###############################################################
#  Generated by:      Cadence Innovus 20.13-s083_1
#  OS:                Linux x86_64(Host ID iron-502-26)
#  Generated on:      Fri Jul  1 13:20:40 2022
#  Design:            puf_super
#  Command:           write_lef_abstract -specifyTopLayer 5 -PGPinLayers {5 6} -noCutObs -extractBlockObs -stripePin results/puf_super.lef
###############################################################

VERSION 5.8 ;

BUSBITCHARS "[]" ;
DIVIDERCHAR "/" ;

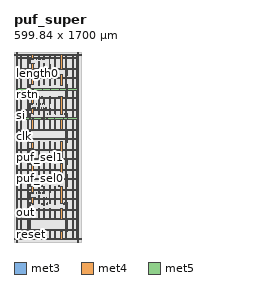
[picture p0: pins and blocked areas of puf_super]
MACRO puf_super
  CLASS BLOCK ;
  SIZE 599.840000 BY 1700.000000 ;
  FOREIGN puf_super 0.000000 0.000000 ;
  ORIGIN 0 0 ;
  SYMMETRY X Y R90 ;
  PIN reset
    DIRECTION INPUT ;
    USE SIGNAL ;
    ANTENNAPARTIALMETALAREA 0.4194 LAYER met3  ;
    ANTENNAPARTIALMETALSIDEAREA 2.68 LAYER met3  ;
    ANTENNAPARTIALCUTAREA 0.04 LAYER via3  ;
    ANTENNAPARTIALMETALAREA 3.9618 LAYER met4  ;
    ANTENNAPARTIALMETALSIDEAREA 21.6 LAYER met4  ;
    ANTENNAMODEL OXIDE1 ;
    ANTENNAGATEAREA 0.495 LAYER met4  ;
    ANTENNAMAXAREACAR 55.6044 LAYER met4  ;
    ANTENNAMAXSIDEAREACAR 280.796 LAYER met4  ;
    ANTENNAMAXCUTCAR 0.323838 LAYER via4  ;
    PORT
      LAYER met3 ;
        RECT 0.000000 0.520000 0.800000 0.820000 ;
    END
  END reset
  PIN clk
    DIRECTION INPUT ;
    USE SIGNAL ;
    ANTENNAPARTIALMETALAREA 15.6204 LAYER met3  ;
    ANTENNAPARTIALMETALSIDEAREA 83.304 LAYER met3  ;
    ANTENNAMODEL OXIDE1 ;
    ANTENNAGATEAREA 1.152 LAYER met3  ;
    ANTENNAMAXAREACAR 14.5083 LAYER met3  ;
    ANTENNAMAXSIDEAREACAR 75.1606 LAYER met3  ;
    ANTENNAMAXCUTCAR 0.0793403 LAYER via3  ;
    PORT
      LAYER met3 ;
        RECT 0.000000 944.190000 0.800000 944.490000 ;
    END
  END clk
  PIN si
    DIRECTION INPUT ;
    USE SIGNAL ;
    ANTENNAPARTIALMETALAREA 23.0986 LAYER met3  ;
    ANTENNAPARTIALMETALSIDEAREA 123.184 LAYER met3  ;
    ANTENNAPARTIALCUTAREA 0.04 LAYER via3  ;
    ANTENNAPARTIALMETALAREA 0.6516 LAYER met4  ;
    ANTENNAPARTIALMETALSIDEAREA 4.416 LAYER met4  ;
    ANTENNAMODEL OXIDE1 ;
    ANTENNAGATEAREA 0.126 LAYER met4  ;
    ANTENNAMAXAREACAR 91.5542 LAYER met4  ;
    ANTENNAMAXSIDEAREACAR 443.786 LAYER met4  ;
    ANTENNAMAXCUTCAR 1.04286 LAYER via4  ;
    PORT
      LAYER met3 ;
        RECT 0.000000 1132.680000 0.800000 1132.980000 ;
    END
  END si
  PIN rstn
    DIRECTION INPUT ;
    USE SIGNAL ;
    ANTENNAPARTIALMETALAREA 33.1464 LAYER met3  ;
    ANTENNAPARTIALMETALSIDEAREA 176.776 LAYER met3  ;
    ANTENNAMODEL OXIDE1 ;
    ANTENNAGATEAREA 2.733 LAYER met3  ;
    ANTENNAMAXAREACAR 44.3132 LAYER met3  ;
    ANTENNAMAXSIDEAREACAR 222.668 LAYER met3  ;
    ANTENNAMAXCUTCAR 0.361584 LAYER via3  ;
    PORT
      LAYER met3 ;
        RECT 0.000000 1321.780000 0.800000 1322.080000 ;
    END
  END rstn
  PIN puf_sel1
    DIRECTION INPUT ;
    USE SIGNAL ;
    ANTENNAPARTIALMETALAREA 1.9584 LAYER met3  ;
    ANTENNAPARTIALMETALSIDEAREA 10.44 LAYER met3  ;
    ANTENNAMODEL OXIDE1 ;
    ANTENNAGATEAREA 0.81 LAYER met3  ;
    ANTENNAMAXAREACAR 69.6004 LAYER met3  ;
    ANTENNAMAXSIDEAREACAR 345.132 LAYER met3  ;
    ANTENNAMAXCUTCAR 0.257059 LAYER via3  ;
    PORT
      LAYER met3 ;
        RECT 0.000000 755.090000 0.800000 755.390000 ;
    END
  END puf_sel1
  PIN puf_sel0
    DIRECTION INPUT ;
    USE SIGNAL ;
    ANTENNAPARTIALMETALAREA 14.3784 LAYER met3  ;
    ANTENNAPARTIALMETALSIDEAREA 76.68 LAYER met3  ;
    ANTENNAMODEL OXIDE1 ;
    ANTENNAGATEAREA 1.5525 LAYER met3  ;
    ANTENNAMAXAREACAR 55.5734 LAYER met3  ;
    ANTENNAMAXSIDEAREACAR 278.761 LAYER met3  ;
    ANTENNAMAXCUTCAR 0.233442 LAYER via3  ;
    PORT
      LAYER met3 ;
        RECT 0.000000 566.600000 0.800000 566.900000 ;
    END
  END puf_sel0
  PIN length1
    DIRECTION INPUT ;
    USE SIGNAL ;
    ANTENNAPARTIALMETALAREA 31.7664 LAYER met3  ;
    ANTENNAPARTIALMETALSIDEAREA 169.416 LAYER met3  ;
    ANTENNAMODEL OXIDE1 ;
    ANTENNAGATEAREA 1.1145 LAYER met3  ;
    ANTENNAMAXAREACAR 150.071 LAYER met3  ;
    ANTENNAMAXSIDEAREACAR 755.32 LAYER met3  ;
    ANTENNAMAXCUTCAR 0.277205 LAYER via3  ;
    PORT
      LAYER met3 ;
        RECT 0.000000 1698.760000 0.800000 1699.060000 ;
    END
  END length1
  PIN length0
    DIRECTION INPUT ;
    USE SIGNAL ;
    ANTENNAPARTIALMETALAREA 28.0404 LAYER met3  ;
    ANTENNAPARTIALMETALSIDEAREA 149.544 LAYER met3  ;
    ANTENNAMODEL OXIDE1 ;
    ANTENNAGATEAREA 1.023 LAYER met3  ;
    ANTENNAMAXAREACAR 140.376 LAYER met3  ;
    ANTENNAMAXSIDEAREACAR 708.093 LAYER met3  ;
    ANTENNAMAXCUTCAR 0.428596 LAYER via3  ;
    PORT
      LAYER met3 ;
        RECT 0.000000 1510.270000 0.800000 1510.570000 ;
    END
  END length0
  PIN out
    DIRECTION OUTPUT ;
    USE SIGNAL ;
    ANTENNADIFFAREA 0.3406 LAYER met3  ;
    ANTENNAPARTIALMETALAREA 8.5824 LAYER met3  ;
    ANTENNAPARTIALMETALSIDEAREA 45.768 LAYER met3  ;
    PORT
      LAYER met3 ;
        RECT 0.000000 189.010000 0.800000 189.310000 ;
    END
  END out
  PIN so
    DIRECTION OUTPUT ;
    USE SIGNAL ;
    ANTENNAPARTIALMETALAREA 141.351 LAYER met3  ;
    ANTENNAPARTIALMETALSIDEAREA 753.856 LAYER met3  ;
    ANTENNAPARTIALCUTAREA 0.08 LAYER via3  ;
    ANTENNAPARTIALMETALAREA 118.617 LAYER met4  ;
    ANTENNAPARTIALMETALSIDEAREA 629.912 LAYER met4  ;
    ANTENNAPARTIALCUTAREA 0.64 LAYER via4  ;
    ANTENNADIFFAREA 0.4455 LAYER met5  ;
    ANTENNAPARTIALMETALAREA 7.44 LAYER met5  ;
    ANTENNAPARTIALMETALSIDEAREA 15 LAYER met5  ;
    PORT
      LAYER met3 ;
        RECT 0.000000 377.500000 0.800000 377.800000 ;
    END
  END so
  PIN vssd1
    DIRECTION INOUT ;
    USE GROUND ;
    PORT
      LAYER met4 ;
        RECT 577.520000 1696.900000 580.620000 1700.000000 ;
    END
    PORT
      LAYER met4 ;
        RECT 577.520000 0.000000 580.620000 3.100000 ;
    END
    PORT
      LAYER met4 ;
        RECT 19.220000 1696.900000 22.320000 1700.000000 ;
    END
    PORT
      LAYER met4 ;
        RECT 19.220000 0.000000 22.320000 3.100000 ;
    END
    PORT
      LAYER met5 ;
        RECT 596.740000 1677.640000 599.840000 1680.740000 ;
    END
    PORT
      LAYER met5 ;
        RECT 0.000000 1677.640000 3.100000 1680.740000 ;
    END
    PORT
      LAYER met5 ;
        RECT 596.740000 19.260000 599.840000 22.360000 ;
    END
    PORT
      LAYER met5 ;
        RECT 0.000000 19.260000 3.100000 22.360000 ;
    END

# P/G power stripe data as pin
    PORT
      LAYER met4 ;
        RECT 19.220000 0.000000 22.320000 1700.000000 ;
        RECT 160.000000 836.695000 170.000000 894.600000 ;
        RECT 260.000000 836.695000 270.000000 894.600000 ;
        RECT 60.000000 19.260000 70.000000 1680.740000 ;
        RECT 577.520000 0.000000 580.620000 1700.000000 ;
        RECT 360.000000 747.890000 370.000000 894.600000 ;
        RECT 460.000000 19.260000 470.000000 1680.740000 ;
        RECT 560.000000 19.260000 570.000000 1680.740000 ;
        RECT 142.800000 392.800000 144.600000 438.495000 ;
        RECT 160.000000 206.320000 170.000000 294.600000 ;
        RECT 260.000000 206.320000 270.000000 300.780000 ;
        RECT 142.800000 92.800000 144.600000 208.120000 ;
        RECT 160.000000 19.260000 170.000000 94.600000 ;
        RECT 260.000000 19.260000 270.000000 94.600000 ;
        RECT 142.800000 292.800000 144.600000 349.690000 ;
        RECT 160.000000 347.890000 170.000000 394.600000 ;
        RECT 174.985000 339.315000 176.785000 349.690000 ;
        RECT 178.405000 392.800000 180.095000 400.845000 ;
        RECT 260.000000 324.320000 270.000000 394.600000 ;
        RECT 291.655000 392.800000 293.345000 400.845000 ;
        RECT 160.000000 606.320000 170.000000 694.600000 ;
        RECT 260.000000 606.320000 270.000000 700.780000 ;
        RECT 142.800000 492.800000 144.600000 608.120000 ;
        RECT 160.000000 436.695000 170.000000 494.600000 ;
        RECT 159.485000 430.450000 161.175000 438.495000 ;
        RECT 169.585000 492.800000 171.385000 502.330000 ;
        RECT 260.000000 436.695000 270.000000 494.600000 ;
        RECT 235.005000 430.450000 236.695000 438.495000 ;
        RECT 216.165000 430.450000 217.855000 438.495000 ;
        RECT 197.275000 430.450000 198.965000 438.495000 ;
        RECT 272.715000 430.450000 274.405000 438.495000 ;
        RECT 253.865000 430.450000 255.555000 438.495000 ;
        RECT 253.005000 492.800000 254.805000 501.735000 ;
        RECT 260.000000 724.320000 270.000000 794.600000 ;
        RECT 174.985000 739.315000 176.785000 749.690000 ;
        RECT 142.800000 692.800000 144.600000 749.690000 ;
        RECT 142.800000 792.800000 144.600000 838.495000 ;
        RECT 160.000000 747.890000 170.000000 794.600000 ;
        RECT 318.655000 392.800000 320.455000 438.495000 ;
        RECT 360.000000 347.890000 370.000000 494.600000 ;
        RECT 360.000000 206.320000 370.000000 294.600000 ;
        RECT 475.940000 92.800000 477.740000 208.120000 ;
        RECT 360.000000 19.260000 370.000000 94.600000 ;
        RECT 477.120000 292.800000 478.920000 349.690000 ;
        RECT 367.485000 339.315000 369.285000 349.690000 ;
        RECT 299.985000 339.315000 301.785000 349.690000 ;
        RECT 449.985000 339.315000 451.785000 349.690000 ;
        RECT 360.000000 606.320000 370.000000 694.600000 ;
        RECT 475.940000 492.800000 477.740000 608.120000 ;
        RECT 405.505000 492.800000 407.305000 501.735000 ;
        RECT 328.005000 598.890000 329.805000 601.420000 ;
        RECT 299.985000 739.315000 301.785000 749.690000 ;
        RECT 367.485000 739.315000 369.285000 749.690000 ;
        RECT 449.985000 739.315000 451.785000 749.690000 ;
        RECT 477.120000 692.800000 478.920000 749.690000 ;
        RECT 318.655000 792.800000 320.455000 838.495000 ;
        RECT 260.000000 1236.695000 270.000000 1294.600000 ;
        RECT 160.000000 1236.695000 170.000000 1294.600000 ;
        RECT 160.000000 1006.320000 170.000000 1094.600000 ;
        RECT 260.000000 1006.320000 270.000000 1100.780000 ;
        RECT 142.800000 892.800000 144.600000 1008.120000 ;
        RECT 260.000000 1124.320000 270.000000 1194.600000 ;
        RECT 160.000000 1147.890000 170.000000 1194.600000 ;
        RECT 142.800000 1092.800000 144.600000 1149.690000 ;
        RECT 176.080000 1139.315000 177.880000 1149.690000 ;
        RECT 142.800000 1192.800000 144.600000 1238.495000 ;
        RECT 178.495000 1192.800000 180.185000 1200.845000 ;
        RECT 159.575000 1230.450000 161.265000 1238.495000 ;
        RECT 291.745000 1192.800000 293.435000 1200.845000 ;
        RECT 197.365000 1230.450000 199.055000 1238.495000 ;
        RECT 216.255000 1230.450000 217.945000 1238.495000 ;
        RECT 235.095000 1230.450000 236.785000 1238.495000 ;
        RECT 253.955000 1230.450000 255.645000 1238.495000 ;
        RECT 272.805000 1230.450000 274.495000 1238.495000 ;
        RECT 160.000000 1406.320000 170.000000 1494.600000 ;
        RECT 260.000000 1406.320000 270.000000 1500.780000 ;
        RECT 142.800000 1292.800000 144.600000 1408.120000 ;
        RECT 169.585000 1292.800000 171.385000 1302.330000 ;
        RECT 253.005000 1292.800000 254.805000 1301.735000 ;
        RECT 142.800000 1592.800000 144.600000 1638.495000 ;
        RECT 260.000000 1524.320000 270.000000 1594.600000 ;
        RECT 160.000000 1547.890000 170.000000 1594.600000 ;
        RECT 178.495000 1592.800000 180.185000 1600.845000 ;
        RECT 291.745000 1592.800000 293.435000 1600.845000 ;
        RECT 142.800000 1492.800000 144.600000 1549.690000 ;
        RECT 160.000000 1636.695000 170.000000 1680.740000 ;
        RECT 159.575000 1630.450000 161.265000 1638.495000 ;
        RECT 260.000000 1636.695000 270.000000 1680.740000 ;
        RECT 216.255000 1630.450000 217.945000 1638.495000 ;
        RECT 197.365000 1630.450000 199.055000 1638.495000 ;
        RECT 235.095000 1630.450000 236.785000 1638.495000 ;
        RECT 253.955000 1630.450000 255.645000 1638.495000 ;
        RECT 272.805000 1630.450000 274.495000 1638.495000 ;
        RECT 360.000000 1147.890000 370.000000 1294.600000 ;
        RECT 360.000000 1006.320000 370.000000 1094.600000 ;
        RECT 475.940000 892.800000 477.740000 1008.120000 ;
        RECT 368.580000 1139.315000 370.380000 1149.690000 ;
        RECT 301.080000 1139.315000 302.880000 1149.690000 ;
        RECT 480.005000 1092.800000 481.805000 1149.690000 ;
        RECT 451.080000 1139.315000 452.880000 1149.690000 ;
        RECT 319.550000 1192.800000 321.350000 1238.495000 ;
        RECT 360.000000 1406.320000 370.000000 1494.600000 ;
        RECT 475.940000 1292.800000 477.740000 1408.120000 ;
        RECT 405.505000 1292.800000 407.305000 1301.735000 ;
        RECT 328.005000 1398.890000 329.805000 1401.420000 ;
        RECT 360.000000 1547.890000 370.000000 1680.740000 ;
        RECT 319.550000 1592.800000 321.350000 1638.495000 ;
        RECT 480.005000 1492.800000 481.805000 1549.690000 ;
        RECT 159.485000 436.695000 170.000000 438.495000 ;
        RECT 160.000000 492.800000 171.385000 494.600000 ;
        RECT 159.575000 1236.695000 170.000000 1238.495000 ;
        RECT 160.000000 1292.800000 171.385000 1294.600000 ;
        RECT 159.575000 1636.695000 170.000000 1638.495000 ;
        RECT 360.000000 1147.890000 370.380000 1149.690000 ;
        RECT 252.360000 100.190000 255.450000 110.000000 ;
        RECT 168.525000 100.370000 172.445000 110.000000 ;
        RECT 178.405000 820.000000 180.095000 830.000000 ;
        RECT 159.485000 820.000000 161.175000 830.000000 ;
        RECT 197.275000 820.000000 198.965000 830.000000 ;
        RECT 216.165000 820.000000 217.855000 830.000000 ;
        RECT 235.005000 820.000000 236.695000 830.000000 ;
        RECT 253.865000 820.000000 255.555000 830.000000 ;
        RECT 272.715000 820.000000 274.405000 830.000000 ;
        RECT 291.655000 820.000000 293.345000 830.000000 ;
        RECT 404.860000 100.190000 407.950000 110.000000 ;
        RECT 327.360000 100.190000 330.450000 110.000000 ;
        RECT 168.525000 999.505000 172.445000 1000.925000 ;
        RECT 252.360000 999.505000 255.450000 1000.925000 ;
        RECT 168.525000 1360.000000 172.445000 1370.000000 ;
        RECT 252.360000 1360.000000 255.450000 1370.000000 ;
        RECT 174.965000 1539.955000 178.995000 1541.375000 ;
        RECT 257.465000 1539.955000 261.495000 1541.375000 ;
        RECT 404.860000 999.505000 407.950000 1000.925000 ;
        RECT 327.360000 999.505000 330.450000 1000.925000 ;
        RECT 404.860000 1360.000000 407.950000 1370.000000 ;
        RECT 327.360000 1360.000000 330.450000 1370.000000 ;
        RECT 367.465000 1539.955000 371.495000 1541.375000 ;
        RECT 299.965000 1539.955000 303.995000 1541.375000 ;
        RECT 449.965000 1539.955000 453.995000 1541.375000 ;
      LAYER met5 ;
        RECT 19.220000 100.000000 580.620000 110.000000 ;
        RECT 0.000000 19.260000 599.840000 22.360000 ;
        RECT 19.220000 280.000000 580.620000 290.000000 ;
        RECT 19.220000 460.000000 580.620000 470.000000 ;
        RECT 19.220000 640.000000 580.620000 650.000000 ;
        RECT 19.220000 820.000000 580.620000 830.000000 ;
        RECT 19.220000 1000.000000 580.620000 1010.000000 ;
        RECT 19.220000 1180.000000 580.620000 1190.000000 ;
        RECT 19.220000 1360.000000 580.620000 1370.000000 ;
        RECT 19.220000 1540.000000 580.620000 1550.000000 ;
        RECT 0.000000 1677.640000 599.840000 1680.740000 ;
        RECT 168.525000 999.505000 172.445000 1000.925000 ;
        RECT 252.360000 999.505000 255.450000 1000.925000 ;
        RECT 174.965000 1539.955000 178.995000 1541.375000 ;
        RECT 257.465000 1539.955000 261.495000 1541.375000 ;
        RECT 404.860000 999.505000 407.950000 1000.925000 ;
        RECT 327.360000 999.505000 330.450000 1000.925000 ;
        RECT 367.465000 1539.955000 371.495000 1541.375000 ;
        RECT 299.965000 1539.955000 303.995000 1541.375000 ;
        RECT 449.965000 1539.955000 453.995000 1541.375000 ;
    END
# end of P/G power stripe data as pin

  END vssd1
  PIN vccd1
    DIRECTION INOUT ;
    USE POWER ;
    PORT
      LAYER met4 ;
        RECT 571.320000 1696.900000 574.420000 1700.000000 ;
    END
    PORT
      LAYER met4 ;
        RECT 571.320000 0.000000 574.420000 3.100000 ;
    END
    PORT
      LAYER met4 ;
        RECT 25.420000 1696.900000 28.520000 1700.000000 ;
    END
    PORT
      LAYER met4 ;
        RECT 25.420000 0.000000 28.520000 3.100000 ;
    END
    PORT
      LAYER met5 ;
        RECT 596.740000 1671.440000 599.840000 1674.540000 ;
    END
    PORT
      LAYER met5 ;
        RECT 0.000000 1671.440000 3.100000 1674.540000 ;
    END
    PORT
      LAYER met5 ;
        RECT 596.740000 25.460000 599.840000 28.560000 ;
    END
    PORT
      LAYER met5 ;
        RECT 0.000000 25.460000 3.100000 28.560000 ;
    END

# P/G power stripe data as pin
    PORT
      LAYER met4 ;
        RECT 120.000000 25.460000 130.000000 1674.540000 ;
        RECT 220.000000 833.095000 230.000000 898.200000 ;
        RECT 25.420000 0.000000 28.520000 1700.000000 ;
        RECT 520.000000 25.460000 530.000000 1674.540000 ;
        RECT 420.000000 744.290000 430.000000 898.200000 ;
        RECT 571.320000 0.000000 574.420000 1700.000000 ;
        RECT 320.000000 840.895000 330.000000 898.200000 ;
        RECT 146.400000 396.400000 148.200000 434.895000 ;
        RECT 220.000000 202.720000 230.000000 298.200000 ;
        RECT 146.400000 96.400000 148.200000 204.520000 ;
        RECT 220.000000 25.460000 230.000000 98.200000 ;
        RECT 146.400000 296.400000 148.200000 346.090000 ;
        RECT 168.270000 339.310000 170.070000 346.090000 ;
        RECT 168.975000 396.400000 170.665000 400.850000 ;
        RECT 187.855000 396.400000 189.545000 400.850000 ;
        RECT 220.000000 344.290000 230.000000 417.360000 ;
        RECT 292.485000 339.315000 294.285000 346.090000 ;
        RECT 249.985000 339.315000 251.785000 346.090000 ;
        RECT 244.405000 396.400000 246.095000 400.850000 ;
        RECT 206.705000 396.400000 208.395000 400.850000 ;
        RECT 263.245000 396.400000 264.935000 400.850000 ;
        RECT 282.225000 396.400000 283.915000 400.850000 ;
        RECT 220.000000 602.720000 230.000000 698.200000 ;
        RECT 146.400000 496.400000 148.200000 604.520000 ;
        RECT 163.005000 496.400000 164.805000 501.735000 ;
        RECT 220.000000 433.095000 230.000000 498.200000 ;
        RECT 245.505000 496.400000 247.305000 501.735000 ;
        RECT 146.400000 696.400000 148.200000 746.090000 ;
        RECT 146.400000 796.400000 148.200000 834.895000 ;
        RECT 187.855000 796.400000 189.545000 800.850000 ;
        RECT 168.975000 796.400000 170.665000 800.850000 ;
        RECT 282.225000 796.400000 283.915000 800.850000 ;
        RECT 263.245000 796.400000 264.935000 800.850000 ;
        RECT 244.405000 796.400000 246.095000 800.850000 ;
        RECT 206.705000 796.400000 208.395000 800.850000 ;
        RECT 220.000000 744.290000 230.000000 817.360000 ;
        RECT 315.055000 396.400000 316.855000 434.895000 ;
        RECT 420.000000 344.290000 430.000000 498.200000 ;
        RECT 420.000000 202.720000 430.000000 298.200000 ;
        RECT 320.000000 202.720000 330.000000 298.200000 ;
        RECT 472.340000 96.400000 474.140000 204.520000 ;
        RECT 320.000000 25.460000 330.000000 98.200000 ;
        RECT 420.000000 25.460000 430.000000 98.200000 ;
        RECT 473.520000 296.400000 475.320000 346.090000 ;
        RECT 320.000000 344.290000 330.000000 390.400000 ;
        RECT 359.985000 339.315000 361.785000 346.090000 ;
        RECT 442.485000 339.315000 444.285000 346.090000 ;
        RECT 420.000000 602.720000 430.000000 698.200000 ;
        RECT 320.000000 602.720000 330.000000 698.200000 ;
        RECT 472.340000 496.400000 474.140000 604.520000 ;
        RECT 320.000000 440.895000 330.000000 498.200000 ;
        RECT 398.005000 496.400000 399.805000 501.735000 ;
        RECT 320.505000 496.400000 322.305000 501.735000 ;
        RECT 473.520000 696.400000 475.320000 746.090000 ;
        RECT 315.055000 796.400000 316.855000 834.895000 ;
        RECT 320.000000 744.290000 330.000000 790.400000 ;
        RECT 220.000000 1233.095000 230.000000 1298.200000 ;
        RECT 220.000000 1002.720000 230.000000 1098.200000 ;
        RECT 146.400000 896.400000 148.200000 1004.520000 ;
        RECT 163.005000 896.400000 164.805000 901.735000 ;
        RECT 245.505000 896.400000 247.305000 901.735000 ;
        RECT 220.000000 1144.290000 230.000000 1217.360000 ;
        RECT 146.400000 1096.400000 148.200000 1146.090000 ;
        RECT 146.400000 1196.400000 148.200000 1234.895000 ;
        RECT 169.065000 1196.400000 170.755000 1200.850000 ;
        RECT 187.945000 1196.400000 189.635000 1200.850000 ;
        RECT 206.795000 1196.400000 208.485000 1200.850000 ;
        RECT 244.495000 1196.400000 246.185000 1200.850000 ;
        RECT 263.335000 1196.400000 265.025000 1200.850000 ;
        RECT 282.315000 1196.400000 284.005000 1200.850000 ;
        RECT 220.000000 1402.720000 230.000000 1498.200000 ;
        RECT 146.400000 1296.400000 148.200000 1404.520000 ;
        RECT 163.005000 1296.400000 164.805000 1301.735000 ;
        RECT 245.505000 1296.400000 247.305000 1301.735000 ;
        RECT 220.000000 1544.290000 230.000000 1617.360000 ;
        RECT 146.400000 1496.400000 148.200000 1546.090000 ;
        RECT 169.365000 1539.310000 171.165000 1546.090000 ;
        RECT 293.580000 1539.315000 295.380000 1546.090000 ;
        RECT 251.080000 1539.315000 252.880000 1546.090000 ;
        RECT 146.400000 1596.400000 148.200000 1634.895000 ;
        RECT 187.945000 1596.400000 189.635000 1600.850000 ;
        RECT 169.065000 1596.400000 170.755000 1600.850000 ;
        RECT 220.000000 1633.095000 230.000000 1674.540000 ;
        RECT 282.315000 1596.400000 284.005000 1600.850000 ;
        RECT 263.335000 1596.400000 265.025000 1600.850000 ;
        RECT 244.495000 1596.400000 246.185000 1600.850000 ;
        RECT 206.795000 1596.400000 208.485000 1600.850000 ;
        RECT 420.000000 1144.290000 430.000000 1298.200000 ;
        RECT 320.000000 1240.895000 330.000000 1298.200000 ;
        RECT 420.000000 1002.720000 430.000000 1098.200000 ;
        RECT 320.000000 1002.720000 330.000000 1098.200000 ;
        RECT 472.340000 896.400000 474.140000 1004.520000 ;
        RECT 320.505000 896.400000 322.305000 901.735000 ;
        RECT 398.005000 896.400000 399.805000 901.735000 ;
        RECT 320.000000 1144.290000 330.000000 1190.400000 ;
        RECT 476.405000 1096.400000 478.205000 1146.090000 ;
        RECT 315.950000 1196.400000 317.750000 1234.895000 ;
        RECT 420.000000 1402.720000 430.000000 1498.200000 ;
        RECT 320.000000 1402.720000 330.000000 1498.200000 ;
        RECT 472.340000 1296.400000 474.140000 1404.520000 ;
        RECT 320.505000 1296.400000 322.305000 1301.735000 ;
        RECT 398.005000 1296.400000 399.805000 1301.735000 ;
        RECT 420.000000 1544.290000 430.000000 1674.540000 ;
        RECT 361.080000 1539.315000 362.880000 1546.090000 ;
        RECT 320.000000 1544.290000 330.000000 1590.400000 ;
        RECT 476.405000 1496.400000 478.205000 1546.090000 ;
        RECT 443.580000 1539.315000 445.380000 1546.090000 ;
        RECT 320.000000 1640.895000 330.000000 1674.540000 ;
        RECT 315.950000 1596.400000 317.750000 1634.895000 ;
        RECT 323.380000 390.075000 330.000000 390.405000 ;
        RECT 162.360000 199.505000 165.450000 200.925000 ;
        RECT 244.860000 199.505000 247.950000 200.925000 ;
        RECT 162.360000 560.000000 165.450000 570.000000 ;
        RECT 244.860000 560.000000 247.950000 570.000000 ;
        RECT 167.155000 739.950000 171.185000 741.370000 ;
        RECT 291.370000 739.955000 295.400000 741.375000 ;
        RECT 248.870000 739.955000 252.900000 741.375000 ;
        RECT 397.360000 199.505000 400.450000 200.925000 ;
        RECT 319.860000 199.505000 322.950000 200.925000 ;
        RECT 397.360000 560.000000 400.450000 570.000000 ;
        RECT 319.860000 560.000000 322.950000 570.000000 ;
        RECT 358.870000 739.955000 362.900000 741.375000 ;
        RECT 441.370000 739.955000 445.400000 741.375000 ;
        RECT 162.360000 920.000000 165.450000 930.000000 ;
        RECT 244.860000 920.000000 247.950000 930.000000 ;
        RECT 168.250000 1102.795000 172.280000 1110.000000 ;
        RECT 292.465000 1102.800000 296.495000 1110.000000 ;
        RECT 249.965000 1102.800000 253.995000 1110.000000 ;
        RECT 397.360000 920.000000 400.450000 930.000000 ;
        RECT 319.860000 920.000000 322.950000 930.000000 ;
        RECT 359.965000 1102.800000 363.995000 1110.000000 ;
        RECT 442.465000 1102.800000 446.495000 1110.000000 ;
      LAYER met5 ;
        RECT 0.000000 25.460000 599.840000 28.560000 ;
        RECT 25.420000 200.000000 574.420000 210.000000 ;
        RECT 25.420000 380.000000 574.420000 390.000000 ;
        RECT 25.420000 560.000000 574.420000 570.000000 ;
        RECT 25.420000 740.000000 574.420000 750.000000 ;
        RECT 25.420000 920.000000 574.420000 930.000000 ;
        RECT 25.420000 1100.000000 574.420000 1110.000000 ;
        RECT 25.420000 1280.000000 574.420000 1290.000000 ;
        RECT 25.420000 1460.000000 574.420000 1470.000000 ;
        RECT 0.000000 1671.440000 599.840000 1674.540000 ;
        RECT 25.420000 1640.000000 574.420000 1650.000000 ;
        RECT 162.360000 199.505000 165.450000 200.925000 ;
        RECT 244.860000 199.505000 247.950000 200.925000 ;
        RECT 167.155000 739.950000 171.185000 741.370000 ;
        RECT 291.370000 739.955000 295.400000 741.375000 ;
        RECT 248.870000 739.955000 252.900000 741.375000 ;
        RECT 397.360000 199.505000 400.450000 200.925000 ;
        RECT 319.860000 199.505000 322.950000 200.925000 ;
        RECT 358.870000 739.955000 362.900000 741.375000 ;
        RECT 441.370000 739.955000 445.400000 741.375000 ;
    END
# end of P/G power stripe data as pin

  END vccd1
  OBS
    LAYER li1 ;
      RECT 0.000000 0.000000 599.840000 1700.000000 ;
    LAYER met1 ;
      RECT 0.000000 0.000000 599.840000 1700.000000 ;
    LAYER met2 ;
      RECT 0.000000 0.000000 599.840000 1700.000000 ;
    LAYER met3 ;
      RECT 0.000000 0.000000 599.840000 1700.000000 ;
    LAYER met4 ;
      RECT 0.000000 0.000000 599.840000 1700.000000 ;
  END
END puf_super

END LIBRARY
